VERSION 5.7 ;
  NOWIREEXTENSIONATPIN ON ;
  DIVIDERCHAR "/" ;
  BUSBITCHARS "[]" ;
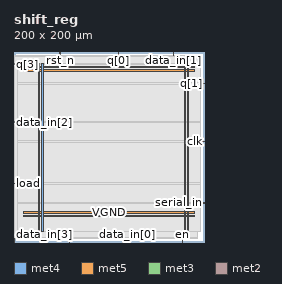
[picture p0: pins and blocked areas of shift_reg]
MACRO shift_reg
  CLASS BLOCK ;
  FOREIGN shift_reg ;
  ORIGIN 0.000 0.000 ;
  SIZE 200.000 BY 200.000 ;
  PIN VGND
    DIRECTION INOUT ;
    USE GROUND ;
    PORT
      LAYER met4 ;
        RECT 28.940 10.640 30.540 187.920 ;
    END
    PORT
      LAYER met4 ;
        RECT 182.540 10.640 184.140 187.920 ;
    END
    PORT
      LAYER met5 ;
        RECT 9.880 30.030 190.220 31.630 ;
    END
    PORT
      LAYER met5 ;
        RECT 9.880 183.210 190.220 184.810 ;
    END
  END VGND
  PIN VPWR
    DIRECTION INOUT ;
    USE POWER ;
    PORT
      LAYER met4 ;
        RECT 25.640 10.640 27.240 187.920 ;
    END
    PORT
      LAYER met4 ;
        RECT 179.240 10.640 180.840 187.920 ;
    END
    PORT
      LAYER met5 ;
        RECT 9.880 26.730 190.220 28.330 ;
    END
    PORT
      LAYER met5 ;
        RECT 9.880 179.910 190.220 181.510 ;
    END
  END VPWR
  PIN clk
    DIRECTION INPUT ;
    USE SIGNAL ;
    ANTENNAGATEAREA 0.852000 ;
    PORT
      LAYER met3 ;
        RECT 196.000 105.440 200.000 106.040 ;
    END
  END clk
  PIN data_in[0]
    DIRECTION INPUT ;
    USE SIGNAL ;
    ANTENNAGATEAREA 0.196500 ;
    PORT
      LAYER met2 ;
        RECT 119.230 0.000 119.510 4.000 ;
    END
  END data_in[0]
  PIN data_in[1]
    DIRECTION INPUT ;
    USE SIGNAL ;
    ANTENNAGATEAREA 0.196500 ;
    PORT
      LAYER met2 ;
        RECT 167.530 196.000 167.810 200.000 ;
    END
  END data_in[1]
  PIN data_in[2]
    DIRECTION INPUT ;
    USE SIGNAL ;
    ANTENNAGATEAREA 0.196500 ;
    PORT
      LAYER met3 ;
        RECT 0.000 125.840 4.000 126.440 ;
    END
  END data_in[2]
  PIN data_in[3]
    DIRECTION INPUT ;
    USE SIGNAL ;
    ANTENNAGATEAREA 0.126000 ;
    PORT
      LAYER met2 ;
        RECT 0.090 0.000 0.370 4.000 ;
    END
  END data_in[3]
  PIN en
    DIRECTION INPUT ;
    USE SIGNAL ;
    ANTENNAGATEAREA 0.159000 ;
    PORT
      LAYER met2 ;
        RECT 177.190 0.000 177.470 4.000 ;
    END
  END en
  PIN load
    DIRECTION INPUT ;
    USE SIGNAL ;
    ANTENNAGATEAREA 0.159000 ;
    PORT
      LAYER met3 ;
        RECT 0.000 61.240 4.000 61.840 ;
    END
  END load
  PIN q[0]
    DIRECTION OUTPUT TRISTATE ;
    USE SIGNAL ;
    ANTENNADIFFAREA 0.795200 ;
    PORT
      LAYER met2 ;
        RECT 109.570 196.000 109.850 200.000 ;
    END
  END q[0]
  PIN q[1]
    DIRECTION OUTPUT TRISTATE ;
    USE SIGNAL ;
    ANTENNADIFFAREA 0.795200 ;
    PORT
      LAYER met3 ;
        RECT 196.000 166.640 200.000 167.240 ;
    END
  END q[1]
  PIN q[2]
    DIRECTION OUTPUT TRISTATE ;
    USE SIGNAL ;
    ANTENNADIFFAREA 0.795200 ;
    PORT
      LAYER met2 ;
        RECT 58.050 0.000 58.330 4.000 ;
    END
  END q[2]
  PIN q[3]
    DIRECTION OUTPUT TRISTATE ;
    USE SIGNAL ;
    ANTENNADIFFAREA 0.795200 ;
    PORT
      LAYER met3 ;
        RECT 0.000 187.040 4.000 187.640 ;
    END
  END q[3]
  PIN rst_n
    DIRECTION INPUT ;
    USE SIGNAL ;
    ANTENNAGATEAREA 0.159000 ;
    PORT
      LAYER met2 ;
        RECT 48.390 196.000 48.670 200.000 ;
    END
  END rst_n
  PIN serial_in
    DIRECTION INPUT ;
    USE SIGNAL ;
    ANTENNAGATEAREA 0.196500 ;
    PORT
      LAYER met3 ;
        RECT 196.000 40.840 200.000 41.440 ;
    END
  END serial_in
  OBS
      LAYER li1 ;
        RECT 10.120 10.795 189.980 187.765 ;
      LAYER met1 ;
        RECT 0.070 10.640 192.670 187.920 ;
      LAYER met2 ;
        RECT 0.100 195.720 48.110 196.000 ;
        RECT 48.950 195.720 109.290 196.000 ;
        RECT 110.130 195.720 167.250 196.000 ;
        RECT 168.090 195.720 192.650 196.000 ;
        RECT 0.100 4.280 192.650 195.720 ;
        RECT 0.650 4.000 57.770 4.280 ;
        RECT 58.610 4.000 118.950 4.280 ;
        RECT 119.790 4.000 176.910 4.280 ;
        RECT 177.750 4.000 192.650 4.280 ;
      LAYER met3 ;
        RECT 4.400 186.640 196.000 187.845 ;
        RECT 4.000 167.640 196.000 186.640 ;
        RECT 4.000 166.240 195.600 167.640 ;
        RECT 4.000 126.840 196.000 166.240 ;
        RECT 4.400 125.440 196.000 126.840 ;
        RECT 4.000 106.440 196.000 125.440 ;
        RECT 4.000 105.040 195.600 106.440 ;
        RECT 4.000 62.240 196.000 105.040 ;
        RECT 4.400 60.840 196.000 62.240 ;
        RECT 4.000 41.840 196.000 60.840 ;
        RECT 4.000 40.440 195.600 41.840 ;
        RECT 4.000 10.715 196.000 40.440 ;
  END
END shift_reg
END LIBRARY

